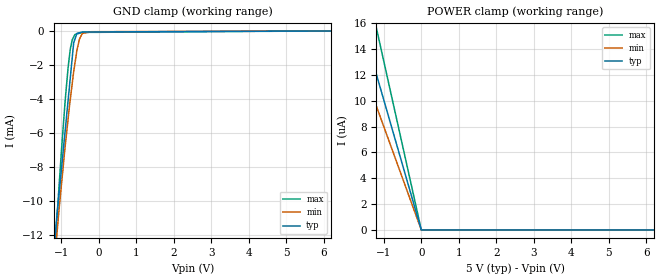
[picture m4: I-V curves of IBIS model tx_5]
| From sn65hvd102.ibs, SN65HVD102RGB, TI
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|   tx_5 Model
[Model]   tx_5
Model_type   Input
Vinl = 0.8
Vinh = 2.0
|   typ   min   max
|   (nom PVT)   (fast PVT)   (slow PVT)
C_comp   8.085e-13   7.971e-13   8.143e-13
| Where nom  PVT is Nominal Process, 5V, 45C
|   Fast PVT is Strong Process,  5.5V, -20C
|   Slow PVT is Weak Process,   4.5V, 125C
[Voltage Range]   5   4.5   5.5
|Junction Temperature
[Temperature Range]   45   125   -20
[Power Clamp Reference]   5   4.5   5.5
[GND Clamp Reference]   0   0   0
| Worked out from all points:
|   GND clamp passes 1 mA (typ) near -0.68 V on its own axis
[GND Clamp]
|   Voltage   I(typ)   I(min)   I(max)
-5V       -180.5mA   -153.2mA   -214mA
-1.243V   -14.43mA   -15.06mA   -15.37mA
-1.14V    -11.36mA   -12.47mA   -11.77mA
-1.105V   -10.58mA   -11.6mA    -10.57mA
-907.5mV  -6.08mA    -6.99mA    -4.384mA
-819.5mV  -4.081mA   -5.162mA   -2.152mA
-759mV    -2.706mA   -3.976mA   -1.031mA
-670mV    -684.2uA   -2.383mA   -343.9uA
-580mV    -132.5uA   -1.098mA   -162.5uA
-441mV    -58.85uA   -137.9uA   -84.51uA
-202.5mV  -52.79uA   -37.78uA   -74.61uA
10V       0A         0A         0A
[POWER Clamp]
|   Voltage   I(typ)   I(min)   I(max)
-5V       50.28uA    39.98uA    65.26uA
-2.192V   22.04uA    17.52uA    28.6uA
-1.375V   13.83uA    11uA       17.95uA
-1.14V    11.46uA    9.117uA    14.88uA
-84.44fV  0A         0A         0A
10V       0A         0A         0A
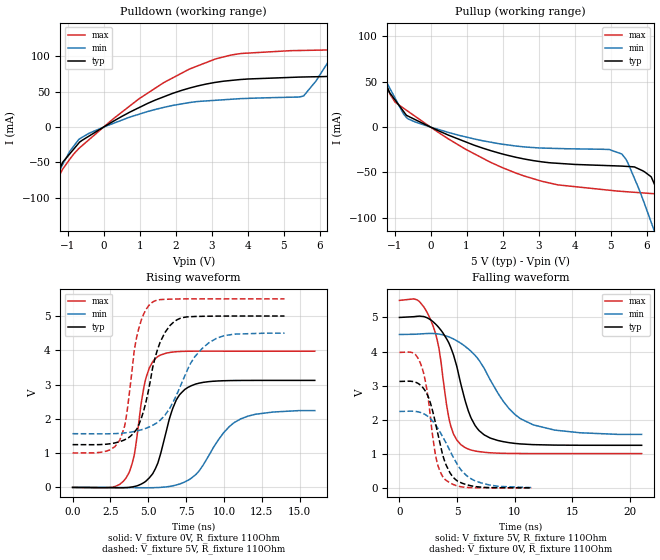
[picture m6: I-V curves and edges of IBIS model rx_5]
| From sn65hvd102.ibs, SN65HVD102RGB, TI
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|   rx_5 Model
[Model]   rx_5
Model_type   Output
Polarity   Inverting
Vmeas = 2.5
Vref = 0
Cref = 2pF
Rref = 200
|   typ   min   max
|   (nom PVT)   (fast PVT)   (slow PVT)
C_comp   2.343e-12   2.300e-12   2.445e-12
| Where nom  PVT is Nominal Process, 5V, 45C
|   Fast PVT is Strong Process,  5.5V, -20C
|   Slow PVT is Weak Process,   4.5V, 125C
[Voltage Range]   5   4.5   5.5
|Junction Temperature
[Temperature Range]   45   125   -20
[Pullup Reference]   5   4.5   5.5
[Pulldown Reference]   0   0   0
[Power Clamp Reference]   5   4.5   5.5
[GND Clamp Reference]   0   0   0
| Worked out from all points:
|   slope of the pulldown table from 0 to 0.75 V, typ, clamps not added: 34.5 ohm
|   slope of the pullup table from 0 to 0.75 V, typ, clamps not added: 58.5 ohm
|   falling waveform, V_fixture 5V, R_fixture 110Ohm: 20-80 % time 2.01ns typ, 3.53ns min, 1.32ns max; typ from 5 V to 1.25 V
|   rising waveform, V_fixture 0V, R_fixture 110Ohm: 20-80 % time 1.25ns typ, 2.11ns min, 850ps max; typ from 0 V to 3.12 V
|   rising waveform, V_fixture 5V, R_fixture 110Ohm: 20-80 % time 1.28ns typ, 2.1ns min, 866ps max; typ from 1.25 V to 5 V
|   falling waveform, V_fixture 0V, R_fixture 110Ohm: 20-80 % time 1.43ns typ, 2.3ns min, 1.01ns max; typ from 3.12 V to 0.001 V
[Pulldown]
|   Voltage   I(typ)   I(min)   I(max)
-5V       -586.9mA   -505.8mA   -714.1mA
-1.87V    -138.8mA   -130.6mA   -160.1mA
-1.14V    -49.98mA   -52.95mA   -59.74mA
-670.5mV  -21.46mA   -16.73mA   -29.53mA
995.5mV   27.88mA    18.42mA    40.5mA
3.08V     63.13mA    37.84mA    95.99mA
5.548V    70.95mA    43.91mA    108.6mA
6.365V    72.11mA    102.6mA    109.3mA
6.872V    109.6mA    143.3mA    109.7mA
7.183V    140mA      169.2mA    111.5mA
8.146V    234mA      249.4mA    219.8mA
10V       416.5mA    403.8mA    450.1mA
[Pullup]
|   Voltage   I(typ)   I(min)   I(max)
-5V       416.2mA    361.7mA    512mA
-2.481V   168.2mA    152.7mA    197.8mA
-1.375V   59.67mA    60.94mA    63.2mA
-984.5mV  29.81mA    31.91mA    27.49mA
-616.5mV  11.91mA    8.825mA    17.1mA
2.376V    -33.34mA   -20.94mA   -50.78mA
5.31V     -43.03mA   -29.66mA   -70.93mA
6.226V    -63.66mA   -115.7mA   -73.54mA
6.6V      -104.7mA   -156.8mA   -83.31mA
6.835V    -134.7mA   -182.6mA   -92.26mA
7.15V     -176.1mA   -219.5mA   -126.4mA
10V       -587mA     -568.4mA   -623.2mA
[Ramp]
R_load = 110
|   typ   min   max
dV/dt_r   1.87326/1.23982e-09   1.34483/2.10078e-09   2.38436/8.46253e-10
dV/dt_f   2.25104/1.99731e-09   1.75889/3.52303e-09   2.69679/1.31439e-09
[Falling Waveform]
V_fixture = 5V
V_fixture_min = 4.5V
V_fixture_max = 5.5V
R_fixture = 110Ohm
|   Time   V(typ)   V(min)   V(max)
0s        5V         4.5V       5.5V
1.548ns   5.034V     4.511V     5.513V
2.668ns   4.938V     4.531V     4.96V
3.438ns   4.693V     4.511V     4.071V
4.444ns   4.124V     4.406V     1.823V
5.658ns   2.607V     4.161V     1.189V
6.228ns   2.038V     3.999V     1.108V
7.3ns     1.567V     3.535V     1.046V
10.49ns   1.289V     2.03V      1.007V
21ns      1.248V     1.569V     1.005V
[Rising Waveform]
V_fixture = 0V
V_fixture_min = 0V
V_fixture_max = 0V
R_fixture = 110Ohm
|   Time   V(typ)   V(min)   V(max)
0s        2.055nV    11.85nV    1.576nV
2.594ns   -7.984mV   -1.306mV   5.637mV
3.532ns   -5.985mV   -4.412mV   276.1mV
4.072ns   26.08mV    -6.748mV   934.4mV
4.84ns    181.9mV    -9.642mV   3.177V
5.648ns   730.1mV    -3.272mV   3.823V
6.626ns   2.312V     46.9mV     3.95V
7.62ns    2.918V     206.7mV    3.973V
11.11ns   3.12V      2V         3.974V
16ns      3.122V     2.241V     3.974V
[Rising Waveform]
V_fixture = 5V
V_fixture_min = 4.5V
V_fixture_max = 5.5V
R_fixture = 110Ohm
|   Time   V(typ)   V(min)   V(max)
0s        1.248V     1.567V     1.005V
3.122ns   1.335V     1.577V     1.384V
3.518ns   1.406V     1.593V     1.98V
4.252ns   1.708V     1.648V     4.416V
5.294ns   3.504V     1.813V     5.408V
5.784ns   4.236V     1.959V     5.479V
6.704ns   4.834V     2.546V     5.496V
7.73ns    4.978V     3.572V     5.5V
9.002ns   4.995V     4.218V     5.5V
14ns      5V         4.5V       5.5V
[Falling Waveform]
V_fixture = 0V
V_fixture_min = 0V
V_fixture_max = 0V
R_fixture = 110Ohm
|   Time   V(typ)   V(min)   V(max)
0s        3.122V     2.241V     3.974V
1.212ns   3.117V     2.248V     3.954V
1.838ns   3.008V     2.21V      3.641V
2.374ns   2.761V     2.12V      2.891V
3.122ns   1.904V     1.85V      964.7mV
3.386ns   1.504V     1.714V     606.9mV
3.904ns   799.8mV    1.405V     262.1mV
4.84ns    250.7mV    793.9mV    75.4mV
6.242ns   57.54mV    258.7mV    5.548mV
11.48ns   1.395mV    7.55mV     129.1uV
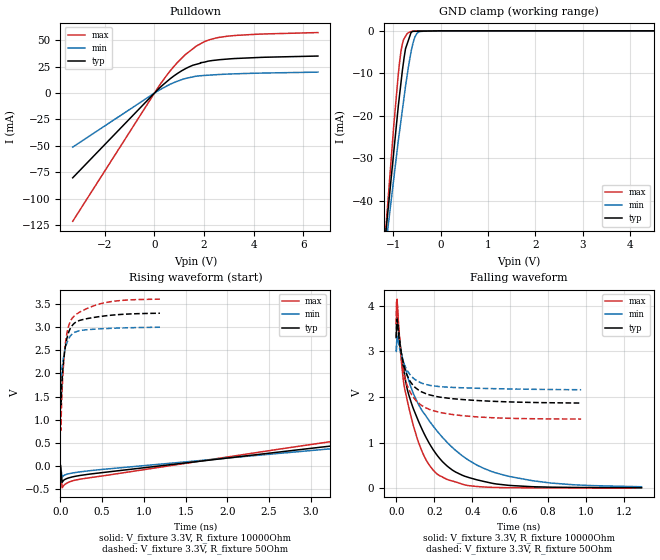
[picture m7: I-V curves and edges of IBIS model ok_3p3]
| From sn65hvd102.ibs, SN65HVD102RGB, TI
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|   ok_3p3 Model
[Model]   ok_3p3
Model_type   Open_drain
Polarity   Inverting
Vmeas = 1.65
Vref = 3.3
Cref = 2pF
Rref = 10000
|   typ   min   max
|   (nom PVT)   (fast PVT)   (slow PVT)
C_comp   1.553e-12   1.546e-12   1.553e-12
| Where nom  PVT is Nominal Process, 3.3V, 45C
|   Fast PVT is Strong Process,  3.6V, -20C
|   Slow PVT is Weak Process,   3V, 125C
[Voltage Range]   3.3   3   3.6
|Junction Temperature
[Temperature Range]   45   125   -20
[Pullup Reference]   3.3   3   3.6
[Pulldown Reference]   0   0   0
[Power Clamp Reference]   3.3   3   3.6
[GND Clamp Reference]   0   0   0
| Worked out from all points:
|   slope of the pulldown table from 0 to 0.495 V, typ, clamps not added: 45.8 ohm
|   GND clamp passes 1 mA (typ) near -0.65 V on its own axis
|   falling waveform, V_fixture 3.3V, R_fixture 10000Ohm: 20-80 % time 187ps typ, 314ps min, 120ps max; typ from 3.3 V to 0.014 V
|   rising waveform, V_fixture 3.3V, R_fixture 10000Ohm: 20-80 % time 28.2ns typ, 29.5ns min, 27.8ns max; typ from 0.014 V to 3.3 V
|   falling waveform, V_fixture 3.3V, R_fixture 50Ohm: 20-80 % time 92.4ps typ, 89.5ps min, 82.8ps max; typ from 3.3 V to 1.87 V
|   rising waveform, V_fixture 3.3V, R_fixture 50Ohm: 20-80 % time 98.9ps typ, 93.1ps min, 110ps max; typ from 1.86 V to 3.29 V
[Pulldown]
|   Voltage   I(typ)   I(min)   I(max)
-3.3V     -80.33mA   -51.22mA   -121.6mA
262.8mV   6.047mA    3.708mA    9.302mA
630mV     13.49mA    8.343mA    20.88mA
939.6mV   18.77mA    11.33mA    29.32mA
1.246V    23.05mA    13.79mA    36.43mA
1.688V    27.25mA    15.99mA    44.49mA
2.167V    30.27mA    16.94mA    50.15mA
2.473V    31.22mA    17.42mA    52.18mA
2.934V    32.22mA    17.97mA    53.87mA
4.162V    33.7mA     18.86mA    55.8mA
6.6V      35.11mA    19.86mA    57.36mA
[GND Clamp]
|   Voltage   I(typ)   I(min)   I(max)
-3.3V     -292.9mA   -257.4mA   -347.1mA
-1.214V   -53.31mA   -55.35mA   -54.63mA
-1.141V   -45.07mA   -48.52mA   -43.52mA
-993.6mV  -28.44mA   -34.75mA   -22.25mA
-867.6mV  -14.72mA   -23.27mA   -7.035mA
-817.2mV  -9.853mA   -19.05mA   -3.337mA
-745.8mV  -4.213mA   -13.06mA   -1.283mA
-630mV    -446.2uA   -5.018mA   -162.9uA
-549mV    -112.4uA   -1.492mA   -56.18uA
-507mV    -103.8uA   -630.6uA   -35.01uA
-285mV    -58.03uA   -2.197uA   -419.7nA
6.6V      0A         0A         0A
[POWER Clamp]
|   Voltage   I(typ)   I(min)   I(max)
-3.3V     0A         0A         0A
0V        0A         0A         0A
6.6V      0A         0A         0A
[Ramp]
R_load = 10000
|   typ   min   max
dV/dt_r   1.97078/2.81276e-08   1.78701/2.94524e-08   2.15308/2.76925e-08
dV/dt_f   1.97172/1.87485e-10   1.78688/3.17585e-10   2.15417/1.19543e-10
[Falling Waveform]
V_fixture = 3.3V
V_fixture_min = 3V
V_fixture_max = 3.6V
R_fixture = 10000Ohm
|   Time   V(typ)   V(min)   V(max)
0s        3.3V       3V         3.6V
2ps       3.614V     3.193V     4.09V
4ps       3.73V      3.311V     4.145V
36ps      2.689V     2.803V     2.413V
90ps      1.745V     2.076V     1.376V
150ps     1.17V      1.621V     679mV
218ps     708.7mV    1.24V      304.9mV
346ps     289.3mV    717.7mV    93.24mV
526ps     95.39mV    336mV      17.81mV
1.292ns   14.44mV    34.47mV    9.712mV
[Rising Waveform]
V_fixture = 3.3V
V_fixture_min = 3V
V_fixture_max = 3.6V
R_fixture = 10000Ohm
|   Time   V(typ)   V(min)   V(max)
0s        13.57mV    19.48mV    9.726mV
20ps      -344.8mV   -236mV     -465.3mV
240ps     -196.8mV   -119.7mV   -276.1mV
4.66ns    691.2mV    584.7mV    824.4mV
16.6ns    1.84V      1.61V      2.053V
27.12ns   2.432V     2.155V     2.689V
39.98ns   2.844V     2.544V     3.125V
54.56ns   3.08V      2.775V     3.373V
74.04ns   3.218V     2.913V     3.515V
150ns     3.298V     2.998V     3.598V
[Falling Waveform]
V_fixture = 3.3V
V_fixture_min = 3V
V_fixture_max = 3.6V
R_fixture = 50Ohm
|   Time   V(typ)   V(min)   V(max)
0s        3.3V       3V         3.6V
2ps       3.606V     3.189V     4.077V
4ps       3.703V     3.295V     4.104V
14ps      3.324V     3.134V     3.423V
24ps      3.022V     2.946V     2.963V
54ps      2.508V     2.61V      2.298V
90ps      2.249V     2.413V     1.997V
144ps     2.095V     2.291V     1.788V
394ps     1.932V     2.196V     1.574V
974ps     1.868V     2.159V     1.517V
[Rising Waveform]
V_fixture = 3.3V
V_fixture_min = 3V
V_fixture_max = 3.6V
R_fixture = 50Ohm
|   Time   V(typ)   V(min)   V(max)
0s        1.861V     2.15V      1.516V
2ps       1.495V     1.974V     1.001V
4ps       1.322V     1.868V     771.7mV
16ps      1.72V      2.036V     1.442V
28ps      2.055V     2.233V     1.922V
60ps      2.586V     2.553V     2.653V
102ps     2.903V     2.758V     3.042V
168ps     3.081V     2.881V     3.241V
578ps     3.246V     2.967V     3.537V
1.192ns   3.295V     2.993V     3.597V
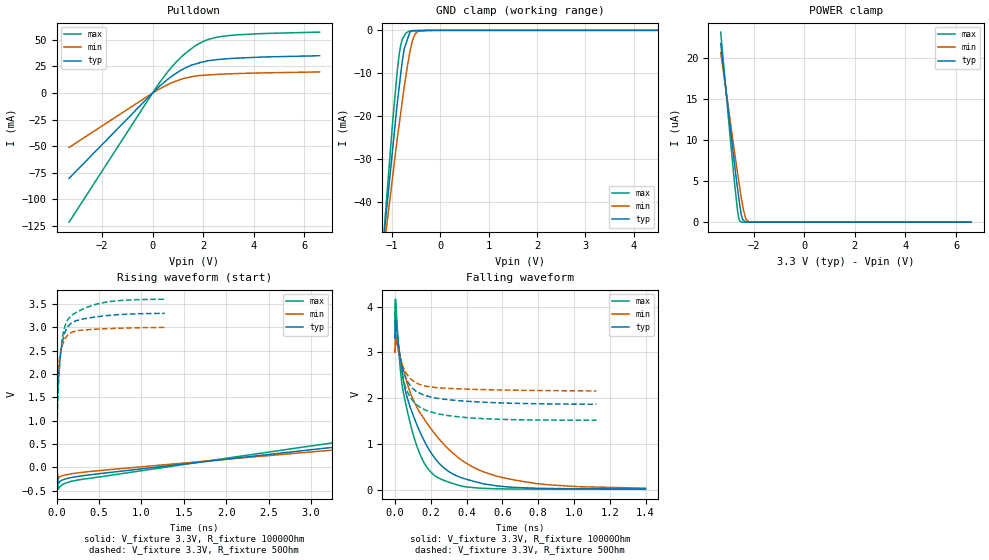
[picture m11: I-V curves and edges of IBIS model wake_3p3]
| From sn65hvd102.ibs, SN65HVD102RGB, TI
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|   wake_3p3 Model
[Model]   wake_3p3
Model_type   Open_drain
Polarity   Inverting
Vmeas = 1.65
Vref = 3.3
Cref = 2pF
Rref = 10000
|   typ   min   max
|   (nom PVT)   (fast PVT)   (slow PVT)
C_comp   1.553e-12   1.546e-12   1.553e-12
| Where nom  PVT is Nominal Process, 3.3V, 45C
|   Fast PVT is Strong Process,  3.6V, -20C
|   Slow PVT is Weak Process,   3V, 125C
[Voltage Range]   3.3   3   3.6
|Junction Temperature
[Temperature Range]   45   125   -20
[Pullup Reference]   3.3   3   3.6
[Pulldown Reference]   0   0   0
[Power Clamp Reference]   3.3   3   3.6
[GND Clamp Reference]   0   0   0
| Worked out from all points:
|   slope of the pulldown table from 0 to 0.495 V, typ, clamps not added: 45.8 ohm
|   GND clamp passes 1 mA (typ) near -0.65 V on its own axis
|   falling waveform, V_fixture 3.3V, R_fixture 10000Ohm: 20-80 % time 189ps typ, 317ps min, 120ps max; typ from 3.3 V to 0.017 V
|   rising waveform, V_fixture 3.3V, R_fixture 10000Ohm: 20-80 % time 29.6ns typ, 31ns min, 29.1ns max; typ from 0.014 V to 3.3 V
|   falling waveform, V_fixture 3.3V, R_fixture 50Ohm: 20-80 % time 94ps typ, 91.3ps min, 83.5ps max; typ from 3.3 V to 1.87 V
|   rising waveform, V_fixture 3.3V, R_fixture 50Ohm: 20-80 % time 100ps typ, 94.3ps min, 112ps max; typ from 1.86 V to 3.29 V
[Pulldown]
|   Voltage   I(typ)   I(min)   I(max)
-3.3V     -80.33mA   -51.22mA   -121.6mA
262.8mV   6.047mA    3.708mA    9.302mA
630mV     13.49mA    8.343mA    20.88mA
939.6mV   18.77mA    11.33mA    29.32mA
1.246V    23.05mA    13.79mA    36.43mA
1.688V    27.25mA    15.99mA    44.49mA
2.167V    30.27mA    16.94mA    50.15mA
2.473V    31.22mA    17.42mA    52.18mA
2.934V    32.22mA    17.97mA    53.87mA
4.162V    33.7mA     18.86mA    55.8mA
6.6V      35.11mA    19.86mA    57.36mA
[GND Clamp]
|   Voltage   I(typ)   I(min)   I(max)
-3.3V     -292.9mA   -257.4mA   -347.2mA
-1.214V   -53.33mA   -55.37mA   -54.65mA
-1.141V   -45.08mA   -48.53mA   -43.53mA
-993.6mV  -28.45mA   -34.76mA   -22.26mA
-867.6mV  -14.73mA   -23.28mA   -7.038mA
-817.2mV  -9.857mA   -19.05mA   -3.339mA
-745.8mV  -4.215mA   -13.07mA   -1.283mA
-630mV    -446.7uA   -5.021mA   -162.9uA
-549mV    -112.6uA   -1.493mA   -56.18uA
-507mV    -103.9uA   -631.1uA   -35.01uA
-285mV    -58.11uA   -2.199uA   -419.7nA
6.6V      0A         0A         0A
[POWER Clamp]
|   Voltage   I(typ)   I(min)   I(max)
-3.3V     21.76uA    20.64uA    23.13uA
-2.974V   12.85uA    13.4uA     11.92uA
-2.761V   7.25uA     8.698uA    4.976uA
-2.646V   4.358uA    6.202uA    1.686uA
-2.603V   3.362uA    5.32uA     759.5nA
-2.563V   2.448uA    4.513uA    240nA
-2.52V    1.541uA    3.631uA    42.78nA
-2.439V   345.7nA    2.131uA    0A
-2.391V   209.8nA    1.357uA    0A
-2.298V   0A         320.5nA    0A
-2.157V   0A         0A         0A
6.6V      0A         0A         0A
[Ramp]
R_load = 10000
|   typ   min   max
dV/dt_r   1.97037/2.95834e-08   1.78654/3.09168e-08   2.15269/2.90092e-08
dV/dt_f   1.9699/1.88564e-10   1.77945/3.17006e-10   2.15308/1.20208e-10
[Falling Waveform]
V_fixture = 3.3V
V_fixture_min = 3V
V_fixture_max = 3.6V
R_fixture = 10000Ohm
C_fixture = 0F
|   Time   V(typ)   V(min)   V(max)
0s        3.3V       3V         3.6V
2ps       3.614V     3.193V     4.09V
4ps       3.729V     3.311V     4.144V
38ps      2.635V     2.771V     2.348V
92ps      1.727V     2.059V     1.351V
153ps     1.152V     1.608V     661.9mV
221ps     700.4mV    1.23V      311.8mV
350ps     294.1mV    713.1mV    103.9mV
568ps     83.7mV     296.4mV    19.92mV
1.399ns   16.84mV    34.25mV    11.53mV
[Rising Waveform]
V_fixture = 3.3V
V_fixture_min = 3V
V_fixture_max = 3.6V
R_fixture = 10000Ohm
|   Time   V(typ)   V(min)   V(max)
0s        13.57mV    19.48mV    9.726mV
20ps      -344mV     -235.5mV   -463.7mV
300ps     -178.3mV   -104.7mV   -254.4mV
4.26ns    617.4mV    519.6mV    727.2mV
10.56ns   1.295V     1.127V     1.456V
17.14ns   1.822V     1.597V     2.033V
28ns      2.415V     2.14V      2.671V
41.16ns   2.828V     2.53V      3.109V
75.52ns   3.21V      2.905V     3.508V
145ns     3.3V       3V         3.6V
[Falling Waveform]
V_fixture = 3.3V
V_fixture_min = 3V
V_fixture_max = 3.6V
R_fixture = 50Ohm
|   Time   V(typ)   V(min)   V(max)
0s        3.3V       3V         3.6V
2ps       3.606V     3.189V     4.077V
4ps       3.702V     3.295V     4.103V
14ps      3.323V     3.134V     3.423V
26ps      2.972V     2.914V     2.891V
58ps      2.469V     2.581V     2.252V
102ps     2.203V     2.376V     1.935V
170ps     2.056V     2.264V     1.74V
430ps     1.925V     2.193V     1.566V
1.126ns   1.866V     2.157V     1.518V
[Rising Waveform]
V_fixture = 3.3V
V_fixture_min = 3V
V_fixture_max = 3.6V
R_fixture = 50Ohm
|   Time   V(typ)   V(min)   V(max)
0s        1.861V     2.15V      1.516V
2ps       1.495V     1.975V     1.001V
4ps       1.322V     1.868V     772.1mV
16ps      1.721V     2.037V     1.443V
28ps      2.056V     2.234V     1.922V
60ps      2.584V     2.552V     2.649V
104ps     2.908V     2.762V     3.047V
174ps     3.085V     2.885V     3.245V
578ps     3.244V     2.966V     3.533V
1.276ns   3.295V     2.993V     3.596V
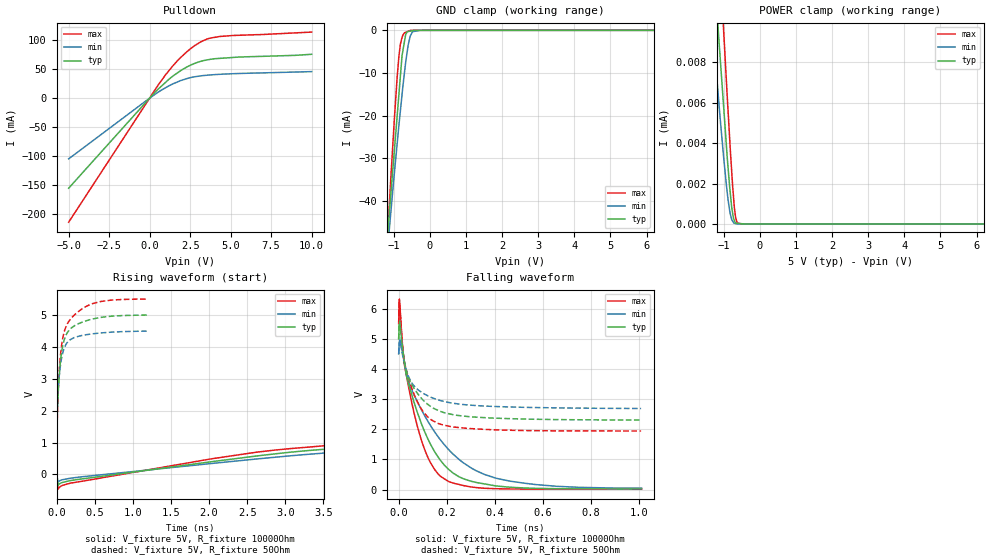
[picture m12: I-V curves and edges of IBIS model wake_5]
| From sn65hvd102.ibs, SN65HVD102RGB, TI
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|   wake_5 Model
[Model]   wake_5
Model_type   Open_drain
Polarity   Inverting
Vmeas = 2.5
Vref = 5
Cref = 2pF
Rref = 10000
|   typ   min   max
|   (nom PVT)   (fast PVT)   (slow PVT)
C_comp   1.593e-12   1.577e-12   1.625e-12
| Where nom  PVT is Nominal Process, 5V, 45C
|   Fast PVT is Strong Process,  5.5V, -20C
|   Slow PVT is Weak Process,   4.5V, 125C
[Voltage Range]   5   4.5   5.5
|Junction Temperature
[Temperature Range]   45   125   -20
[Pullup Reference]   5   4.5   5.5
[Pulldown Reference]   0   0   0
[Power Clamp Reference]   5   4.5   5.5
[GND Clamp Reference]   0   0   0
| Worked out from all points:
|   slope of the pulldown table from 0 to 0.75 V, typ, clamps not added: 35.3 ohm
|   GND clamp passes 1 mA (typ) near -0.67 V on its own axis
|   falling waveform, V_fixture 5V, R_fixture 10000Ohm: 20-80 % time 142ps typ, 219ps min, 99.2ps max; typ from 5 V to 0.022 V
|   rising waveform, V_fixture 5V, R_fixture 10000Ohm: 20-80 % time 29ns typ, 30.2ns min, 28.6ns max; typ from 0.016 V to 5 V
|   falling waveform, V_fixture 5V, R_fixture 50Ohm: 20-80 % time 98.2ps typ, 112ps min, 80ps max; typ from 5 V to 2.31 V
|   rising waveform, V_fixture 5V, R_fixture 50Ohm: 20-80 % time 117ps typ, 106ps min, 135ps max; typ from 2.31 V to 4.99 V
[Pulldown]
|   Voltage   I(typ)   I(min)   I(max)
-5V       -155.5mA   -104.9mA   -214.2mA
555.5mV   16.29mA    10.79mA    23.77mA
1.413V    37.57mA    24.3mA     55.1mA
1.875V    46.72mA    29.8mA     69.12mA
2.376V    54.89mA    34.39mA    82mA
2.811V    60.31mA    36.99mA    91.18mA
3.278V    64.46mA    38.86mA    98.87mA
3.735V    66.94mA    40.02mA    103.6mA
4.34V     68.66mA    41.14mA    106.5mA
10V       75.7mA     45.78mA    114mA
[GND Clamp]
|   Voltage   I(typ)   I(min)   I(max)
-5V       -441.1mA   -407.4mA   -497mA
-1.373V   -72.16mA   -70.32mA   -78.82mA
-1.14V    -44.6mA    -48.28mA   -43.58mA
-1.083V   -38.69mA   -42.93mA   -35.02mA
-984.5mV  -28.33mA   -33.61mA   -21.02mA
-913mV    -20.86mA   -27.24mA   -11.89mA
-858mV    -15.1mA    -22.34mA   -6.173mA
-770mV    -5.899mA   -15.04mA   -1.625mA
-670mV    -989.3uA   -7.52mA    -448.5uA
-544.5mV  -191.6uA   -1.371mA   -21.14uA
-274.5mV  -876.6nA   -1.634uA   -1.497uA
10V       0A         0A         0A
[POWER Clamp]
|   Voltage   I(typ)   I(min)   I(max)
-5V       117.8uA    95.97uA    151uA
-1.369V   15.43uA    11.07uA    22.07uA
-1.183V   10.4uA     7.02uA     15.62uA
-1.14V    9.258uA    6.1uA      14.18uA
-1.012V   6.042uA    3.486uA    9.88uA
-877.5mV  2.722uA    1.162uA    5.508uA
-780mV    835.4nA    219nA      2.602uA
-709.5mV  186.5nA    41.54nA    882.5nA
-670.5mV  42.55nA    12.15nA    309.8nA
-621.5mV  33.14nA    0A         45.64nA
-500.5mV  11.76nA    0A         0A
10V       0A         0A         0A
[Ramp]
R_load = 10000
|   typ   min   max
dV/dt_r   2.98723/2.89938e-08   2.68359/3.01102e-08   3.28923/2.86149e-08
dV/dt_f   2.98839/1.42387e-10   2.68253/2.217e-10   3.29143/9.92024e-11
[Falling Waveform]
V_fixture = 5V
V_fixture_min = 4.5V
V_fixture_max = 5.5V
R_fixture = 10000Ohm
|   Time   V(typ)   V(min)   V(max)
0s        5V         4.5V       5.5V
3ps       5.598V     4.908V     6.317V
24ps      4.193V     4.212V     4.131V
46ps      3.374V     3.485V     3.209V
93ps      2.22V      2.672V     1.676V
136ps     1.448V     2.077V     841.8mV
188ps     828.8mV    1.506V     365.7mV
270ps     356.7mV    881.8mV    132.3mV
410ps     116.6mV    367.7mV    28.49mV
1.01ns    21.51mV    47.84mV    14.28mV
[Rising Waveform]
V_fixture = 5V
V_fixture_min = 4.5V
V_fixture_max = 5.5V
R_fixture = 10000Ohm
|   Time   V(typ)   V(min)   V(max)
0s        15.91mV    21.46mV    12.17mV
20ps      -341mV     -237mV     -459.6mV
3.08ns    700.8mV    588mV      814.1mV
9.78ns    1.839V     1.587V     2.075V
16.78ns   2.729V     2.376V     3.055V
27.22ns   3.627V     3.192V     4.029V
39.64ns   4.25V      3.773V     4.699V
53.7ns    4.624V     4.128V     5.098V
72.24ns   4.849V     4.347V     5.338V
140ns     4.995V     4.494V     5.494V
[Falling Waveform]
V_fixture = 5V
V_fixture_min = 4.5V
V_fixture_max = 5.5V
R_fixture = 50Ohm
|   Time   V(typ)   V(min)   V(max)
0s        5V         4.5V       5.5V
2ps       5.467V     4.792V     6.215V
4ps       5.566V     4.931V     6.189V
14ps      4.812V     4.554V     4.957V
24ps      4.241V     4.181V     4.228V
64ps      3.361V     3.438V     3.157V
106ps     2.93V      3.173V     2.541V
162ps     2.632V     2.98V      2.203V
372ps     2.379V     2.765V     1.991V
1.008ns   2.308V     2.689V     1.943V
[Rising Waveform]
V_fixture = 5V
V_fixture_min = 4.5V
V_fixture_max = 5.5V
R_fixture = 50Ohm
|   Time   V(typ)   V(min)   V(max)
0s        2.306V     2.68V      1.946V
2ps       1.827V     2.338V     1.354V
4ps       1.573V     2.119V     1.19V
18ps      2.355V     2.55V      2.331V
32ps      2.975V     2.997V     3.084V
70ps      3.88V      3.686V     4.1V
108ps     4.266V     4V         4.525V
172ps     4.537V     4.208V     4.834V
476ps     4.872V     4.407V     5.354V
1.182ns   4.993V     4.49V      5.494V
